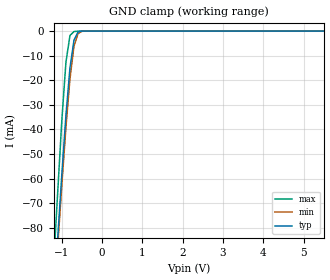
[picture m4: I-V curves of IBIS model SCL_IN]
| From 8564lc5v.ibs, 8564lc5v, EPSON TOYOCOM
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|   Model INPUT
[Model]   SCL_IN
Model_type   Input
Polarity   Non-Inverting
Vinl =   1.5V
Vinh =   3.5V
C_comp   5pF   5pF   5pF
[Temperature Range]   25.00   85.00   -40.00
[Voltage Range]   5.0V   4.5V   5.50V
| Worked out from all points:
|   GND clamp passes 1 mA (typ) near -0.62 V on its own axis
[GND_clamp]
| voltage   I(typ)   I(min)   I(max)
-5.5V     -1.203A    -1.168A    -1.323A
-1.2V     -108.7mA   -111.3mA   -93.1mA
-1.1V     -83.3mA    -86.7mA    -64.5mA
-1V       -57.9mA    -62.2mA    -35.9mA
-900mV    -34.4mA    -39.3mA    -12.8mA
-800mV    -15mA      -19.5mA    -1.8mA
-700mV    -3.7mA     -6.2mA     -200uA
-600mV    -400uA     -1mA       0A
-500mV    0A         -100uA     0A
5.5V      0A         0A         0A
